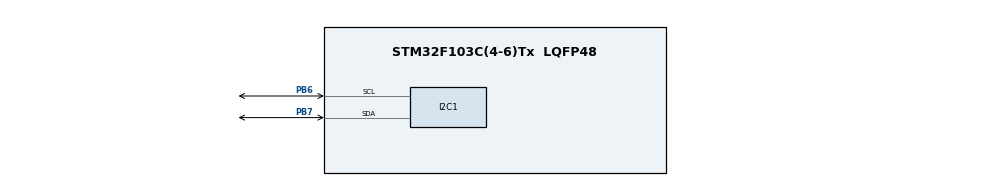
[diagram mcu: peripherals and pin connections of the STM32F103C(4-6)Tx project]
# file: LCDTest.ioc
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Mcu.Family=STM32F1
Mcu.Name=STM32F103C(4-6)Tx
Mcu.Package=LQFP48
NVIC.PriorityGroup=NVIC_PRIORITYGROUP_4
PB6.Mode=I2C
PB6.Signal=I2C1_SCL
PB7.Mode=I2C
PB7.Signal=I2C1_SDA
ProjectManager.HeapSize=0x200
ProjectManager.StackSize=0x400
ProjectManager.TargetToolchain=STM32CubeIDE
RCC.APB1Freq_Value=8000000
RCC.APB2Freq_Value=8000000
VP_SYS_VS_ND.Mode=No_Debug
board=custom

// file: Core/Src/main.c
/* USER CODE BEGIN Header */
/**
  ******************************************************************************
  * @file           : main.c
  * @brief          : Main program body
  ******************************************************************************
  * @attention
  *
  * <h2><center>&copy; Copyright (c) 2021 STMicroelectronics.
  * All rights reserved.</center></h2>
  *
  * This software component is licensed by ST under BSD 3-Clause license,
  * the "License"; You may not use this file except in compliance with the
  * License. You may obtain a copy of the License at:
  *                        opensource.org/licenses/BSD-3-Clause
  *
  ******************************************************************************
  */
/* USER CODE END Header */
#include "main.h"
#include "i2c.h"
#include "gpio.h"

/* USER CODE BEGIN Includes */
#include "i2c-lcd.h"
/* USER CODE END Includes */

void SystemClock_Config(void);

int main(void)
{

  /* MCU Configuration--------------------------------------------------------*/

  /* Reset of all peripherals, Initializes the Flash interface and the Systick. */
  HAL_Init();

  /* Configure the system clock */
  SystemClock_Config();

  /* Initialize all configured peripherals */
  MX_GPIO_Init();
  MX_I2C1_Init();
  /* USER CODE BEGIN 2 */
  HAL_Delay(1000);

  uint8_t iicAddress = 0;

	uint8_t i2c_frame_data[4]; //test data
	i2c_frame_data[0] = 0b11110001;
//	i2c_frame_data[1] = data_u|0x08;  //en=0, rs=0
//	i2c_frame_data[2] = data_l|0x0C;  //en=1, rs=0
//	i2c_frame_data[3] = data_l|0x08;  //en=0, rs=0
	HAL_StatusTypeDef status;

	HAL_Delay(10);
	status = HAL_I2C_Master_Transmit(&hi2c1, 39, (uint8_t *) i2c_frame_data, 1, 100);
	if (status != HAL_BUSY)
	{
		iicAddress = 39;
	}

	while(1)
	{

		HAL_Delay(10);
		status = HAL_I2C_Master_Transmit(&hi2c1, iicAddress, (uint8_t *) i2c_frame_data, 1, 100);
		if (status != HAL_BUSY)
		{
			break;
		}
		iicAddress ++;
		if (iicAddress == 0)
		{
			break;
		}
	}

//	i2c_frame_data[0] = 0b11110010;
//	status = HAL_I2C_Master_Transmit(&hi2c1, iicAddress, (uint8_t *) i2c_frame_data, 1, 1000);
//
//	i2c_frame_data[0] = 0b11110100;
//	status = HAL_I2C_Master_Transmit(&hi2c1, iicAddress, (uint8_t *) i2c_frame_data, 1, 1000);

//  lcd_init();
//  lcd_send_string("Hello World!");
//  HAL_Delay(1000);
//  lcd_put_cur(1, 0);
//  lcd_send_string("from Cedr1c");

  /* USER CODE END 2 */

  /* Infinite loop */
  while (1)
  {

  }
}

void SystemClock_Config(void)
{
  RCC_OscInitTypeDef RCC_OscInitStruct = {0};
  RCC_ClkInitTypeDef RCC_ClkInitStruct = {0};

  /** Initializes the RCC Oscillators according to the specified parameters
  * in the RCC_OscInitTypeDef structure.
  */
  RCC_OscInitStruct.OscillatorType = RCC_OSCILLATORTYPE_HSE;
  RCC_OscInitStruct.HSEState = RCC_HSE_ON;
  RCC_OscInitStruct.HSEPredivValue = RCC_HSE_PREDIV_DIV1;
  RCC_OscInitStruct.HSIState = RCC_HSI_ON;
  RCC_OscInitStruct.PLL.PLLState = RCC_PLL_ON;
  RCC_OscInitStruct.PLL.PLLSource = RCC_PLLSOURCE_HSE;
  RCC_OscInitStruct.PLL.PLLMUL = RCC_PLL_MUL2;
  if (HAL_RCC_OscConfig(&RCC_OscInitStruct) != HAL_OK)
  {
    Error_Handler();
  }
  /** Initializes the CPU, AHB and APB buses clocks
  */
  RCC_ClkInitStruct.ClockType = RCC_CLOCKTYPE_HCLK|RCC_CLOCKTYPE_SYSCLK
                              |RCC_CLOCKTYPE_PCLK1|RCC_CLOCKTYPE_PCLK2;
  RCC_ClkInitStruct.SYSCLKSource = RCC_SYSCLKSOURCE_PLLCLK;
  RCC_ClkInitStruct.AHBCLKDivider = RCC_SYSCLK_DIV1;
  RCC_ClkInitStruct.APB1CLKDivider = RCC_HCLK_DIV1;
  RCC_ClkInitStruct.APB2CLKDivider = RCC_HCLK_DIV1;

  if (HAL_RCC_ClockConfig(&RCC_ClkInitStruct, FLASH_LATENCY_0) != HAL_OK)
  {
    Error_Handler();
  }
}

void Error_Handler(void)
{
  __disable_irq();
  while (1)
  {
  }
}

/************************ (C) COPYRIGHT STMicroelectronics *****END OF FILE****/
